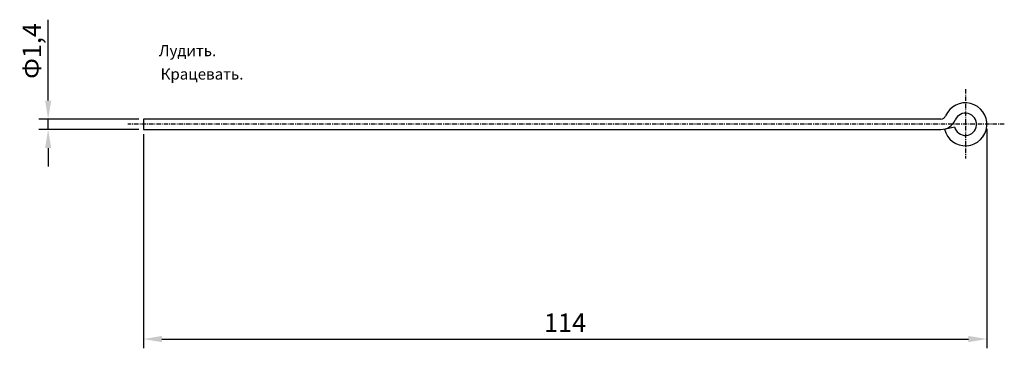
# Model space of a CAD drawing. Units: millimetres. Extents: x 129 to 262, y 115 to 159.
import ezdxf

# ---------------------------------------------------------------- set-up
doc = ezdxf.new("R2010")
doc.units = ezdxf.units.MM
doc.header["$LTSCALE"] = 0.2
doc.linetypes.add('ACAD_ISO10W100', pattern=[18, 12, -3, 0, -3])
doc.dimstyles.new('ISO-25', dxfattribs={"dimtxt": 2.5, "dimasz": 2.5, "dimexe": 1.25, "dimexo": 0.625, "dimtad": 1, "dimtxsty": 'Standard', "dimcen": 2.5, "dimadec": 0, "dimazin": 0, "dimtfac": 1, "dimtmove": 0, "dimatfit": 3, "dimfxl": 0, "dimarcsym": 0})

# ---------------------------------------------------------------- blocks, each defined once
blk = doc.blocks.new('*D2')
at = {"color": 0, "lineweight": -2, "ltscale": 0.25}
for p, q in [((146, 143.83), (146, 114.91)), ((260, 144.53), (260, 114.91)), ((148.5, 116.16), (257.5, 116.16))]:
    blk.add_line(p, q, dxfattribs=at)
at = {"color": 0, "lineweight": 25, "ltscale": 0.25}
for points in [[(148.5, 116.58), (148.5, 115.74), (146, 116.16)], [(257.5, 116.58), (257.5, 115.74), (260, 116.16)]]:
    blk.add_solid(points, dxfattribs=at)
at = {"layer": 'Defpoints', "color": 0, "lineweight": 25, "ltscale": 0.25}
for p in [(260, 145.15), (146, 144.45), (260, 116.16)]:
    blk.add_point(p, dxfattribs=at)
at = {"color": 0, "lineweight": 25, "ltscale": 0.25, "insert": (203, 118.04), "char_height": 2.5, "attachment_point": 5}
blk.add_mtext('114', dxfattribs=at)
blk = doc.blocks.new('*D3')
at = {"color": 0, "lineweight": -2, "ltscale": 0.25}
for p, q in [((133.13, 148.35), (133.13, 159.28)), ((145.38, 145.85), (131.88, 145.85)), ((133.13, 144.45), (133.13, 145.85)), ((145.38, 144.45), (131.88, 144.45)), ((133.13, 141.95), (133.13, 139.45))]:
    blk.add_line(p, q, dxfattribs=at)
at = {"color": 0, "lineweight": 15, "ltscale": 0.25}
for points in [[(132.72, 148.35), (133.55, 148.35), (133.13, 145.85)], [(132.72, 141.95), (133.55, 141.95), (133.13, 144.45)]]:
    blk.add_solid(points, dxfattribs=at)
at = {"layer": 'Defpoints', "color": 0, "lineweight": 15, "ltscale": 0.25}
for p in [(133.13, 145.85), (146, 145.85), (146, 144.45)]:
    blk.add_point(p, dxfattribs=at)
at = {"color": 0, "lineweight": 15, "ltscale": 0.25, "insert": (130.93, 155.06), "char_height": 2.5, "attachment_point": 5, "rotation": 90}
blk.add_mtext('{\\fTahoma|b0|i0|c204|p32;Ф1,4}', dxfattribs=at)

msp = doc.modelspace()

# ---------------------------------------------------------------- linework, layer by layer
at = {"color": 1, "linetype": 'ACAD_ISO10W100', "lineweight": 25, "ltscale": 0.25}
for p, q in [((257.1, 149.902), (257.1, 140.553)), ((262.359, 145.153), (143.906, 145.153))]:
    msp.add_line(p, q, dxfattribs=at)
at = {"color": 7, "lineweight": 30, "ltscale": 0.25}
for p, q in [((146, 145.853), (146, 144.453)), ((253.783, 145.853), (146, 145.853)), ((146, 145.303), (146, 145.003)), ((146, 144.453), (253.783, 144.453)), ((254.249, 144.505), (255.637, 144.821))]:
    msp.add_line(p, q, dxfattribs=at)
for centre, radius, start, end in [((257.1, 145.153), 2.9, 192.79724, 157.11462), ((257.1, 145.153), 1.5, 192.79995, 157.11462), ((253.783, 146.553), 0.7, 270, 337.11462), ((253.783, 146.553), 2.1, 270, 337.11462)]:
    msp.add_arc(centre, radius, start, end, dxfattribs=at)

# ---------------------------------------------------------------- texts
for s, p in [('Лудить.', (148.094, 154.345)), ('Крацевать.', (148.33, 151.193))]:
    msp.add_text(s, height=1.5, dxfattribs=at).set_placement(p)

# ---------------------------------------------------------------- dimensions: what is measured, and where the dimension line sits
at = {"color": 3, "lineweight": 15, "ltscale": 0.25}
dim = msp.add_linear_dim(base=(133.134, 145.853), p1=(146, 144.453), p2=(146, 145.853), angle=90, text='{\\fTahoma|b0|i0|c204|p32;Ф1,4}', dimstyle='ISO-25', dxfattribs=at)
dim.commit()
dim.dimension.update_dxf_attribs({"geometry": '*D3', "text_midpoint": (130.928, 155.064)})
at = {"color": 3, "lineweight": 25, "ltscale": 0.25}
dim = msp.add_linear_dim(base=(260, 116.161), p1=(146, 144.453), p2=(260, 145.153), dimstyle='ISO-25', dxfattribs=at)
dim.commit()
dim.dimension.update_dxf_attribs({"geometry": '*D2', "text_midpoint": (203, 118.036)})

doc.saveas('drawing.dxf')
